VERSION 5.7 ;
  NOWIREEXTENSIONATPIN ON ;
  DIVIDERCHAR "/" ;
  BUSBITCHARS "[]" ;
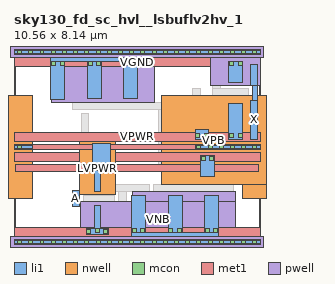
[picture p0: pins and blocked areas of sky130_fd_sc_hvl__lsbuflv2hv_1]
MACRO sky130_fd_sc_hvl__lsbuflv2hv_1
  CLASS BLOCK ;
  FOREIGN sky130_fd_sc_hvl__lsbuflv2hv_1 ;
  ORIGIN 0.000 0.000 ;
  SIZE 10.560 BY 8.140 ;
  PIN A
    ANTENNAGATEAREA 0.252000 ;
    PORT
      LAYER li1 ;
        RECT 2.495 1.530 2.805 2.200 ;
    END
  END A
  PIN LVPWR
    ANTENNADIFFAREA 0.982800 ;
    PORT
      LAYER nwell ;
        RECT 2.800 2.015 4.335 4.325 ;
      LAYER li1 ;
        RECT 3.345 3.225 4.115 4.200 ;
        RECT 3.435 3.075 4.115 3.225 ;
        RECT 3.435 2.165 3.705 3.075 ;
      LAYER mcon ;
        RECT 3.485 3.050 3.655 3.220 ;
        RECT 3.845 3.105 4.015 3.275 ;
      LAYER met1 ;
        RECT 0.070 3.020 10.490 3.305 ;
    END
  END LVPWR
  PIN VGND
    USE GROUND ;
    PORT
      LAYER li1 ;
        RECT 1.585 7.715 5.295 7.885 ;
        RECT 1.585 6.085 2.175 7.715 ;
        RECT 3.145 6.165 3.735 7.715 ;
        RECT 4.705 6.165 5.295 7.715 ;
        RECT 9.210 6.835 9.800 7.745 ;
      LAYER mcon ;
        RECT 1.615 7.545 1.785 7.715 ;
        RECT 1.975 7.545 2.145 7.715 ;
        RECT 3.175 7.545 3.345 7.715 ;
        RECT 3.535 7.545 3.705 7.715 ;
        RECT 4.735 7.545 4.905 7.715 ;
        RECT 5.095 7.545 5.265 7.715 ;
        RECT 9.240 7.545 9.410 7.715 ;
        RECT 9.600 7.545 9.770 7.715 ;
      LAYER met1 ;
        RECT 0.000 7.515 10.560 7.885 ;
    END
    PORT
      LAYER li1 ;
        RECT 3.435 0.565 3.705 1.575 ;
        RECT 3.095 0.335 4.045 0.565 ;
        RECT 5.050 0.425 5.640 1.975 ;
        RECT 6.610 0.425 7.200 1.975 ;
        RECT 8.170 0.425 8.760 1.975 ;
        RECT 5.050 0.255 8.760 0.425 ;
      LAYER mcon ;
        RECT 3.125 0.365 3.295 0.535 ;
        RECT 3.485 0.425 3.655 0.595 ;
        RECT 3.845 0.365 4.015 0.535 ;
        RECT 5.080 0.425 5.250 0.595 ;
        RECT 5.440 0.425 5.610 0.595 ;
        RECT 6.640 0.425 6.810 0.595 ;
        RECT 7.000 0.425 7.170 0.595 ;
        RECT 8.200 0.425 8.370 0.595 ;
        RECT 8.560 0.425 8.730 0.595 ;
      LAYER met1 ;
        RECT 0.000 0.255 10.560 0.625 ;
    END
  END VGND
  PIN VNB
    ANTENNADIFFAREA 1.795200 ;
    PORT
      LAYER pwell ;
        RECT 5.090 1.725 9.500 2.165 ;
        RECT 2.855 0.215 9.500 1.725 ;
        RECT -0.130 -0.215 10.690 0.215 ;
      LAYER li1 ;
        RECT 0.000 -0.085 10.560 0.085 ;
      LAYER mcon ;
        RECT 0.155 -0.085 0.325 0.085 ;
        RECT 0.635 -0.085 0.805 0.085 ;
        RECT 1.115 -0.085 1.285 0.085 ;
        RECT 1.595 -0.085 1.765 0.085 ;
        RECT 2.075 -0.085 2.245 0.085 ;
        RECT 2.555 -0.085 2.725 0.085 ;
        RECT 3.035 -0.085 3.205 0.085 ;
        RECT 3.515 -0.085 3.685 0.085 ;
        RECT 3.995 -0.085 4.165 0.085 ;
        RECT 4.475 -0.085 4.645 0.085 ;
        RECT 4.955 -0.085 5.125 0.085 ;
        RECT 5.435 -0.085 5.605 0.085 ;
        RECT 5.915 -0.085 6.085 0.085 ;
        RECT 6.395 -0.085 6.565 0.085 ;
        RECT 6.875 -0.085 7.045 0.085 ;
        RECT 7.355 -0.085 7.525 0.085 ;
        RECT 7.835 -0.085 8.005 0.085 ;
        RECT 8.315 -0.085 8.485 0.085 ;
        RECT 8.795 -0.085 8.965 0.085 ;
        RECT 9.275 -0.085 9.445 0.085 ;
        RECT 9.755 -0.085 9.925 0.085 ;
        RECT 10.235 -0.085 10.405 0.085 ;
      LAYER met1 ;
        RECT 0.000 -0.115 10.560 0.115 ;
    END
    PORT
      LAYER pwell ;
        RECT -0.130 7.925 10.690 8.355 ;
        RECT 1.625 5.975 6.035 7.925 ;
        RECT 8.425 6.725 10.540 7.925 ;
      LAYER li1 ;
        RECT 0.000 8.055 10.560 8.225 ;
      LAYER mcon ;
        RECT 0.155 8.055 0.325 8.225 ;
        RECT 0.635 8.055 0.805 8.225 ;
        RECT 1.115 8.055 1.285 8.225 ;
        RECT 1.595 8.055 1.765 8.225 ;
        RECT 2.075 8.055 2.245 8.225 ;
        RECT 2.555 8.055 2.725 8.225 ;
        RECT 3.035 8.055 3.205 8.225 ;
        RECT 3.515 8.055 3.685 8.225 ;
        RECT 3.995 8.055 4.165 8.225 ;
        RECT 4.475 8.055 4.645 8.225 ;
        RECT 4.955 8.055 5.125 8.225 ;
        RECT 5.435 8.055 5.605 8.225 ;
        RECT 5.915 8.055 6.085 8.225 ;
        RECT 6.395 8.055 6.565 8.225 ;
        RECT 6.875 8.055 7.045 8.225 ;
        RECT 7.355 8.055 7.525 8.225 ;
        RECT 7.835 8.055 8.005 8.225 ;
        RECT 8.315 8.055 8.485 8.225 ;
        RECT 8.795 8.055 8.965 8.225 ;
        RECT 9.275 8.055 9.445 8.225 ;
        RECT 9.755 8.055 9.925 8.225 ;
        RECT 10.235 8.055 10.405 8.225 ;
      LAYER met1 ;
        RECT 0.000 8.025 10.560 8.255 ;
    END
  END VNB
  PIN VPB
    ANTENNADIFFAREA 0.563550 ;
    PORT
      LAYER nwell ;
        RECT -0.330 1.885 0.800 6.255 ;
        RECT 6.335 2.465 10.890 6.255 ;
        RECT 9.800 1.885 10.890 2.465 ;
      LAYER li1 ;
        RECT 0.000 3.985 0.800 4.155 ;
        RECT 7.755 3.985 10.560 4.155 ;
      LAYER mcon ;
        RECT 0.155 3.985 0.325 4.155 ;
        RECT 7.835 3.985 8.005 4.155 ;
        RECT 8.315 3.985 8.485 4.155 ;
        RECT 8.795 3.985 8.965 4.155 ;
        RECT 9.275 3.985 9.445 4.155 ;
        RECT 9.755 3.985 9.925 4.155 ;
        RECT 10.235 3.985 10.405 4.155 ;
      LAYER met1 ;
        RECT 0.000 3.955 10.560 4.185 ;
    END
  END VPB
  PIN VPWR
    USE POWER ;
    PORT
      LAYER li1 ;
        RECT 7.755 4.405 8.345 4.800 ;
        RECT 9.210 4.405 9.800 5.945 ;
      LAYER mcon ;
        RECT 7.785 4.495 7.955 4.665 ;
        RECT 8.145 4.495 8.315 4.665 ;
        RECT 9.240 4.495 9.410 4.665 ;
        RECT 9.600 4.495 9.770 4.665 ;
      LAYER met1 ;
        RECT 0.000 4.325 10.560 4.695 ;
    END
    PORT
      LAYER li1 ;
        RECT 8.005 2.795 8.595 3.705 ;
      LAYER mcon ;
        RECT 8.035 3.475 8.205 3.645 ;
        RECT 8.395 3.475 8.565 3.645 ;
      LAYER met1 ;
        RECT 0.000 3.445 10.560 3.815 ;
    END
  END VPWR
  PIN X
    ANTENNADIFFAREA 0.596250 ;
    PORT
      LAYER li1 ;
        RECT 10.120 6.725 10.450 7.625 ;
        RECT 10.210 6.055 10.450 6.725 ;
        RECT 10.120 4.405 10.450 6.055 ;
    END
  END X
  OBS
      LAYER li1 ;
        RECT 2.495 5.995 2.825 7.545 ;
        RECT 4.055 5.995 4.385 7.545 ;
        RECT 5.615 5.995 5.945 7.625 ;
        RECT 8.515 6.555 8.845 7.625 ;
        RECT 7.660 5.995 7.990 6.555 ;
        RECT 2.495 5.665 7.990 5.995 ;
        RECT 2.885 3.055 3.175 5.495 ;
        RECT 6.185 3.465 6.515 5.665 ;
        RECT 7.660 5.205 7.990 5.665 ;
        RECT 8.515 6.225 10.040 6.555 ;
        RECT 6.685 4.470 7.495 4.800 ;
        RECT 7.165 3.805 7.495 4.470 ;
        RECT 8.515 4.405 8.845 6.225 ;
        RECT 6.185 3.135 6.995 3.465 ;
        RECT 2.885 2.765 3.265 3.055 ;
        RECT 2.975 1.995 3.265 2.765 ;
        RECT 3.875 2.475 4.185 2.905 ;
        RECT 6.665 2.795 6.995 3.135 ;
        RECT 7.165 3.395 7.835 3.805 ;
        RECT 7.165 2.475 7.495 3.395 ;
        RECT 3.875 2.165 5.790 2.475 ;
        RECT 4.480 2.145 5.790 2.165 ;
        RECT 5.960 2.145 9.410 2.475 ;
        RECT 2.975 1.745 4.310 1.995 ;
        RECT 2.975 0.735 3.265 1.745 ;
        RECT 4.480 1.575 4.810 2.145 ;
        RECT 3.875 1.245 4.810 1.575 ;
        RECT 3.875 0.735 4.185 1.245 ;
        RECT 5.960 0.595 6.290 2.145 ;
        RECT 7.520 0.595 7.850 2.145 ;
        RECT 9.080 0.515 9.410 2.145 ;
  END
END sky130_fd_sc_hvl__lsbuflv2hv_1
END LIBRARY

